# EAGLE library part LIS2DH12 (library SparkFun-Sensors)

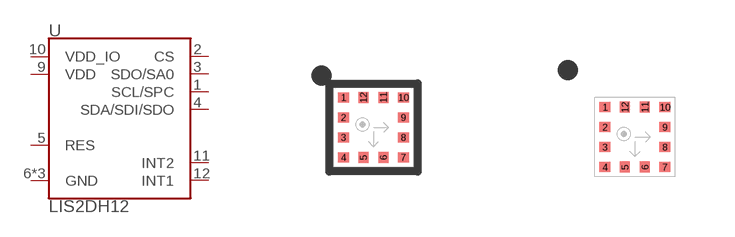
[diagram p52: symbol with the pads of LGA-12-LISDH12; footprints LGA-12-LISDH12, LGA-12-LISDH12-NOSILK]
Designator prefix U

## LIS2DH12 (DIGIKEY: 497-14851-2-ND; PROD_ID: IC-14229)  [LGA-12-LISDH12]
1  SCL/SPC
2  CS
3  SDO/SA0
4  SDA/SDI/SDO
5  RES
6  GND
7  GND
8  GND
9  VDD
10  VDD_IO
11  INT2
12  INT1

## LIS2DH12NS (PROD_ID: IC-14229)  [LGA-12-LISDH12-NOSILK]
Pads as for LGA-12-LISDH12

## Footprint LGA-12-LISDH12 (pad centres in mm)
smd 0.275 x 0.25: 1 -0.75,0.75; 2 -0.75,0.25; 3 -0.75,-0.25; 4 -0.75,-0.75; 7 0.75,-0.75; 8 0.75,-0.25; 9 0.75,0.25; 10 0.75,0.75
smd 0.25 x 0.275: 5 -0.25,-0.75; 6 0.25,-0.75; 11 0.25,0.75; 12 -0.25,0.75

## Footprint LGA-12-LISDH12-NOSILK (pad centres in mm)
smd 0.275 x 0.25: 1 -0.75,0.75; 2 -0.75,0.25; 3 -0.75,-0.25; 4 -0.75,-0.75; 7 0.75,-0.75; 8 0.75,-0.25; 9 0.75,0.25; 10 0.75,0.75
smd 0.25 x 0.275: 5 -0.25,-0.75; 6 0.25,-0.75; 11 0.25,0.75; 12 -0.25,0.75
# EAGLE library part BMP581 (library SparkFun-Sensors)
Bosch BMP581 Pressure Sensor Senses pressure from 300 hPa to 1250 hPa, sends data out over I2C or SPI

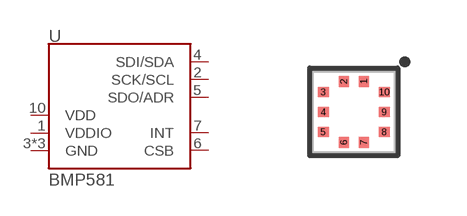
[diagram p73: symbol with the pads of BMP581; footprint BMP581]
Designator prefix U

## BMP581 (PROD_ID: IC-16798)  [BMP581]
1  VDDIO  pwr
2  SCK/SCL
3  GND  pwr
4  SDI/SDA
5  SDO/ADR
6  CSB  in
7  INT  out
8  GND  pwr
9  GND  pwr
10  VDD  pwr

## Footprint BMP581 (pad centres in mm)
LGA10 Specifications: Pin count: 10 Pin pitch: .5mm Area: 2.0 x 2.0 mm Datasheet referenced for footprint
smd 0.25 x 0.275: 1 0.25,0.762; 2 -0.25,0.762; 6 -0.25,-0.762; 7 0.25,-0.762
smd 0.275 x 0.25: 3 -0.762,0.5; 4 -0.762,0; 5 -0.762,-0.5; 8 0.762,-0.5; 9 0.762,0; 10 0.762,0.5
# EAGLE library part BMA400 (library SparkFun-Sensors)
Bosch BMA400 Accelerometer Senses acceleration with 12-bit resolution up to 16g, sends data out over I2C or SPI

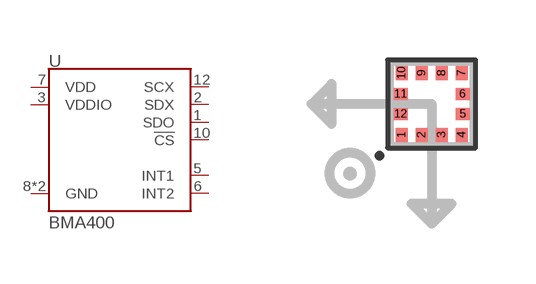
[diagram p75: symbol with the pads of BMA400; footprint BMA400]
Designator prefix U

## BMA400 (PROD_ID: IC-17118)  [BMA400]
1  SDO  out
2  SDX
3  VDDIO  pwr
5  INT1  out
6  INT2  out
7  VDD  pwr
8  GND  pwr
9  GND  pwr
10  !CS!  in
12  SCX  in

## Footprint BMA400 (pad centres in mm)
LGA12 Specifications: Pin count: 12 Pin pitch: .5mm Area: 2.0 x 2.0 mm Datasheet referenced for footprint
smd 0.3 x 0.35: 1 -0.75,-0.775; 2 -0.25,-0.775; 3 0.25,-0.775; 4 0.75,-0.775; 7 0.75,0.775; 8 0.25,0.775; 9 -0.25,0.775; 10 -0.75,0.775
smd 0.35 x 0.3: 5 0.775,-0.25; 6 0.775,0.25; 11 -0.775,0.25; 12 -0.775,-0.25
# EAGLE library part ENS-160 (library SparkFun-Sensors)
ScioSense Indoor Air Quality Sensor - ENS160 The ENS160 is a digital multi-gas sensor solution, based on metal oxide (MOX) technology with four sensor elements. The independent hotplate control allows the detection of a wide range of volatile organic compounds (VOCs) including ethanol, toluene, hydrogen and oxidizing gases with superior sensitivity. The ENS160 supports intelligent algorithms to process raw sensor measurements on-chip. These algorithms calculate CO2-equivalents, TVOC, air quality indices (AQIs) and perform humidity and temperature compensation, as well as baseline management, all on chip.

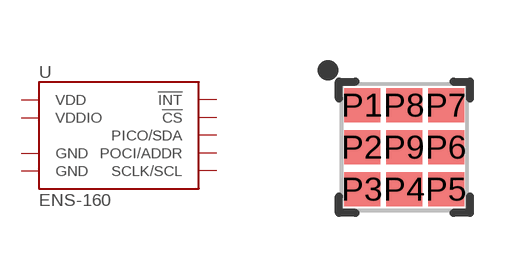
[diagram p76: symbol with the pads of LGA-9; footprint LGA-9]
Designator prefix U

## ENS-160 (PROD_ID: IC-17100; VALUE: ENS160)  [LGA-9]
P1  PICO/SDA
P2  SCLK/SCL
P3  POCI/ADDR
P4  VDD  pwr
P5  VDDIO  pwr
P6  !INT!
P7  !CS!
P8  GND  pwr
P9  GND  pwr

## Footprint LGA-9 (pad centres in mm)
LGA-9 Mechanical Specifications: Pad Size: .9mm x .85mm Pin count: 9 Pin pitch: 1.05mm Package Size: 3mm x 3mm Datasheet referenced for footprint
smd 0.9 x 0.85: P1 -1.085,1.03; P2 -1.085,-0.02; P3 -1.085,-1.07; P4 -0.035,-1.07; P5 1.015,-1.07; P6 1.015,-0.02; P7 1.015,1.03; P8 -0.035,1.03; P9 -0.035,-0.02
